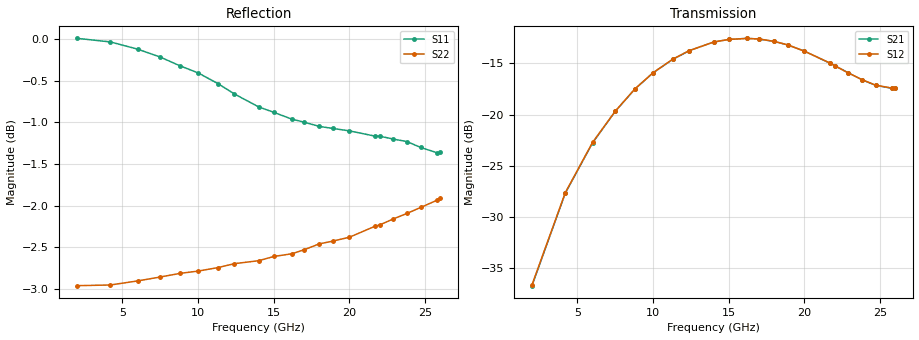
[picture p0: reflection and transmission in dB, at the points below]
! CHUO DENSHI KOGYO Co.,Ltd.
! 1. March 2016
! CKRF7520CK34
! N-channel HJ-FET
! Vds = 0 V Vgs = 0 V
# Hz S  MA  R 50
!  f  S11  S21  S12  S22
!  Hz  MAG  ANG  MAG  ANG  MAG  ANG  MAG  ANG
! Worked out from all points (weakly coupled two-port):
!   241 points, 2 GHz to 26 GHz, reference 50 ohm
!   highest |S21| = -12.55 dB at 16.2 GHz (marker M1); lowest = -36.7 dB at 2 GHz (marker M2)
!   lowest |S11| = -1.4 dB at 25.8 GHz (marker M3), VSWR 12.75, Z = 11.5 - j68.7 ohm
!   |S11| at or under -10 dB: nowhere
!   |S22| runs from -3.0 to -1.9 dB; largest |S21 - S12| = 0.0013
!   S11 on the Smith chart (normalised r, x): 2 GHz: -0.01, -4.20; 7.5 GHz: 0.02, -0.79; 12.4 GHz: 0.04, +0.02; 17 GHz: 0.10, +0.89; 21.7 GHz: 5.02, +7.00; 26 GHz: 0.21, -1.27
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2e9  1.001 -26.8  0.01461 95.3  0.01477 95.1  0.7111 152.8
4.2e9  0.9961 -56.6  0.04136 86.4  0.04159 86.7  0.7118 123.5
6e9  0.9862 -81.8  0.07278 71.4  0.07318 71.6  0.7158 99.7
7.5e9  0.9754 -103.7  0.1038 55.8  0.1039 55.8  0.7197 80.1
8.8e9  0.9637 -123.1  0.1334 40.9  0.1336 41.0  0.7233 63.4
1e10  0.9543 -142.1  0.1601 25.7  0.1601 25.7  0.7256 48.2
1.13e10  0.9404 -163.4  0.1862 8.8  0.1866 8.9  0.7291 32.2
1.24e10  0.9269 178.0  0.2055 -5.9  0.2055 -5.9  0.7331 18.8
1.4e10  0.9105 150.2  0.2262 -28.5  0.2262 -28.3  0.7361 -0.3
1.5e10  0.9037 132.3  0.2329 -42.6  0.233 -42.5  0.7404 -12.1
1.62e10  0.8952 110.7  0.2358 -59.9  0.2356 -59.9  0.7432 -26.4
1.7e10  0.8915 96.1  0.234 -71.9  0.2342 -71.7  0.7473 -35.9
1.8e10  0.8863 77.9  0.2278 -86.9  0.228 -86.9  0.7534 -48.1
1.89e10  0.8838 61.7  0.2191 -100.8  0.2191 -100.7  0.7563 -59.3
2e10  0.8808 41.7  0.2043 -118.5  0.2042 -118.3  0.7604 -73.3
2.17e10  0.8744 10.8  0.1783 -147.1  0.1785 -146.8  0.7721 -95.8
2.2e10  0.8744 5.2  0.1736 -152.4  0.1735 -152.2  0.7734 -100.0
2.29e10  0.8709 -11.7  0.16 -169.0  0.1599 -168.8  0.7799 -112.7
2.38e10  0.8679 -29.4  0.1482 173.6  0.1483 173.7  0.7858 -125.7
2.47e10  0.8609 -47.4  0.1391 155.1  0.1394 155.3  0.7923 -139.3
2.58e10  0.8545 -71.1  0.1344 132.1  0.1347 132.3  0.8004 -155.9
2.6e10  0.855 -75.3  0.1346 128.0  0.1344 128.3  0.8023 -159.1
